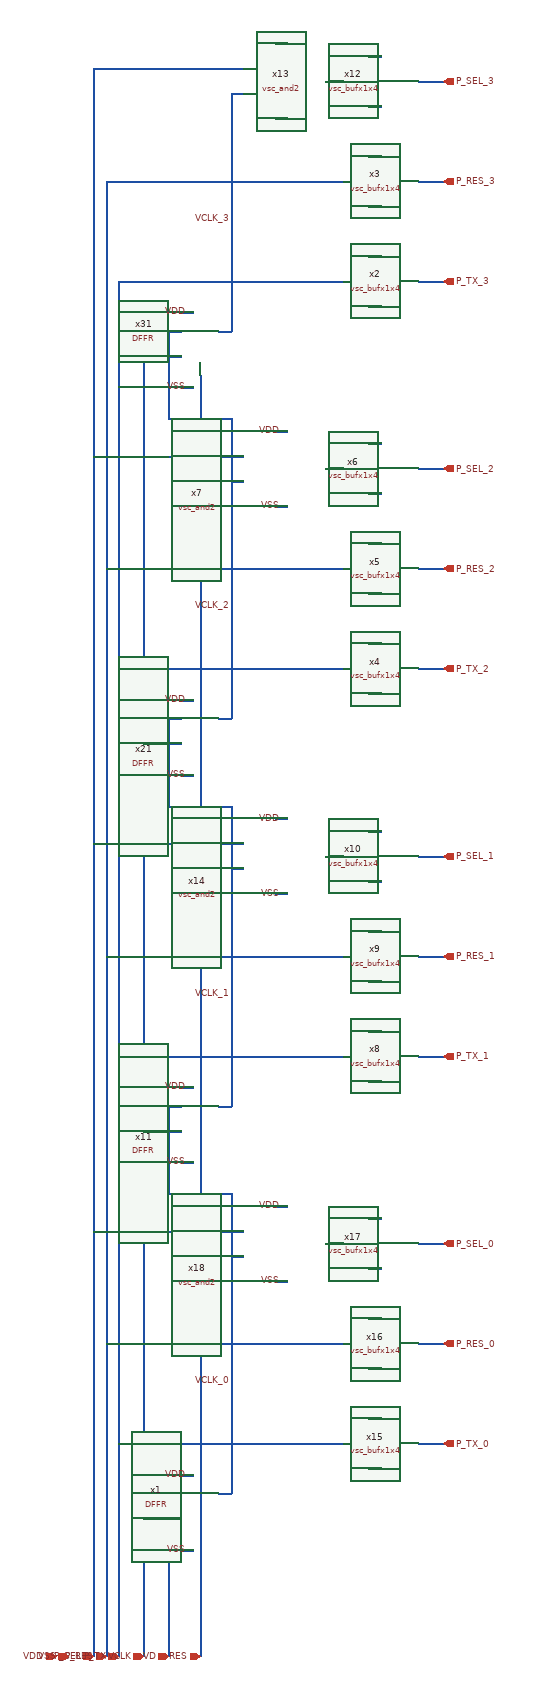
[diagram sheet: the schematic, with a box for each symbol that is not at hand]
v {xschem version=3.4.8RC file_version=1.2}
G {}
K {}
V {}
S {}
E {}
N 80 -2620 80 -80 {lab=P_SEL}
N 100 -2440 100 -80 {lab=P_RES}
N 120 -2280 120 -80 {lab=P_TX}
N 220 -370 240 -370 {lab=VDD}
N 220 -250 240 -250 {lab=VSS}
N 200 -340 200 -80 {lab=VD}
N 160 -2160 160 -80 {lab=VCLK}
N 250 -2130 250 -80 {lab=RES}
N 280 -340 300 -340 {lab=VCLK_0}
N 300 -820 300 -340 {lab=VCLK_0}
N 200 -340 220 -340 {lab=VD}
N 160 -300 220 -300 {lab=VCLK}
N 300 -720 320 -720 {lab=VCLK_0}
N 120 -420 480 -420 {lab=P_TX}
N 100 -580 480 -580 {lab=P_RES}
N 80 -760 320 -760 {lab=P_SEL}
N 600 -420 640 -420 {lab=P_TX_0}
N 600 -580 640 -580 {lab=P_RES_0}
N 600 -740 640 -740 {lab=P_SEL_0}
N 220 -990 240 -990 {lab=VDD}
N 220 -870 240 -870 {lab=VSS}
N 200 -820 300 -820 {lab=VCLK_0}
N 200 -960 200 -820 {lab=VCLK_0}
N 200 -960 220 -960 {lab=VCLK_0}
N 280 -960 300 -960 {lab=VCLK_1}
N 300 -1440 300 -960 {lab=VCLK_1}
N 300 -1340 320 -1340 {lab=VCLK_1}
N 120 -1040 480 -1040 {lab=P_TX}
N 100 -1200 480 -1200 {lab=P_RES}
N 80 -1380 320 -1380 {lab=P_SEL}
N 600 -1040 640 -1040 {lab=P_TX_1}
N 600 -1200 640 -1200 {lab=P_RES_1}
N 600 -1360 640 -1360 {lab=P_SEL_1}
N 220 -1610 240 -1610 {lab=VDD}
N 220 -1490 240 -1490 {lab=VSS}
N 200 -1440 300 -1440 {lab=VCLK_1}
N 200 -1580 200 -1440 {lab=VCLK_1}
N 200 -1580 220 -1580 {lab=VCLK_1}
N 280 -1580 300 -1580 {lab=VCLK_2}
N 300 -2060 300 -1580 {lab=VCLK_2}
N 300 -1960 320 -1960 {lab=VCLK_2}
N 120 -1660 480 -1660 {lab=P_TX}
N 100 -1820 480 -1820 {lab=P_RES}
N 80 -2000 320 -2000 {lab=P_SEL}
N 600 -1660 640 -1660 {lab=P_TX_2}
N 600 -1820 640 -1820 {lab=P_RES_2}
N 600 -1980 640 -1980 {lab=P_SEL_2}
N 220 -2230 240 -2230 {lab=VDD}
N 220 -2110 240 -2110 {lab=VSS}
N 200 -2060 300 -2060 {lab=VCLK_2}
N 200 -2200 200 -2060 {lab=VCLK_2}
N 200 -2200 220 -2200 {lab=VCLK_2}
N 280 -2200 300 -2200 {lab=VCLK_3}
N 300 -2580 300 -2200 {lab=VCLK_3}
N 370 -2540 390 -2540 {lab=VSS}
N 370 -2660 390 -2660 {lab=VDD}
N 300 -2580 320 -2580 {lab=VCLK_3}
N 120 -2280 480 -2280 {lab=P_TX}
N 100 -2440 480 -2440 {lab=P_RES}
N 80 -2620 320 -2620 {lab=P_SEL}
N 520 -2240 540 -2240 {lab=VSS}
N 520 -2320 540 -2320 {lab=VDD}
N 600 -2280 640 -2280 {lab=P_TX_3}
N 600 -2440 640 -2440 {lab=P_RES_3}
N 450 -2600 480 -2600 {lab=#net1}
N 600 -2600 640 -2600 {lab=P_SEL_3}
N 160 -2160 220 -2160 {lab=VCLK}
N 160 -1540 220 -1540 {lab=VCLK}
N 160 -920 220 -920 {lab=VCLK}
N 520 -2400 540 -2400 {lab=VSS}
N 520 -2480 540 -2480 {lab=VDD}
N 520 -2560 540 -2560 {lab=VSS}
N 520 -2640 540 -2640 {lab=VDD}
N 370 -1920 390 -1920 {lab=VSS}
N 370 -2040 390 -2040 {lab=VDD}
N 520 -1620 540 -1620 {lab=VSS}
N 520 -1700 540 -1700 {lab=VDD}
N 450 -1980 480 -1980 {lab=#net1}
N 520 -1780 540 -1780 {lab=VSS}
N 520 -1860 540 -1860 {lab=VDD}
N 520 -1940 540 -1940 {lab=VSS}
N 520 -2020 540 -2020 {lab=VDD}
N 370 -1300 390 -1300 {lab=VSS}
N 370 -1420 390 -1420 {lab=VDD}
N 520 -1000 540 -1000 {lab=VSS}
N 520 -1080 540 -1080 {lab=VDD}
N 450 -1360 480 -1360 {lab=#net1}
N 520 -1160 540 -1160 {lab=VSS}
N 520 -1240 540 -1240 {lab=VDD}
N 520 -1320 540 -1320 {lab=VSS}
N 520 -1400 540 -1400 {lab=VDD}
N 370 -680 390 -680 {lab=VSS}
N 370 -800 390 -800 {lab=VDD}
N 520 -380 540 -380 {lab=VSS}
N 520 -460 540 -460 {lab=VDD}
N 450 -740 480 -740 {lab=#net1}
N 520 -540 540 -540 {lab=VSS}
N 520 -620 540 -620 {lab=VDD}
N 520 -700 540 -700 {lab=VSS}
N 520 -780 540 -780 {lab=VDD}
C {devices/ipin.sym} 80 -80 3 0 {name=p1 lab=P_SEL}
C {devices/ipin.sym} 100 -80 3 0 {name=p2 lab=P_RES}
C {devices/ipin.sym} 120 -80 3 0 {name=p3 lab=P_TX}
C {devices/ipin.sym} 200 -80 3 0 {name=p4 lab=VD}
C {devices/ipin.sym} 160 -80 3 0 {name=p5 lab=VCLK}
C {devices/ipin.sym} 250 -80 3 0 {name=p6 lab=RES}
C {TR-1um_5_stdcell/DFFR.sym} 250 -310 0 0 {name=x1}
C {devices/iopin.sym} 20 -80 1 0 {name=p7 lab=VDD}
C {devices/iopin.sym} 40 -80 1 0 {name=p8 lab=VSS}
C {devices/lab_wire.sym} 230 -370 0 0 {name=p9 sig_type=std_logic lab=VDD}
C {devices/lab_wire.sym} 230 -250 2 1 {name=p10 sig_type=std_logic lab=VSS}
C {devices/opin.sym} 640 -420 0 0 {name=p21 lab=P_TX_0}
C {devices/opin.sym} 640 -580 0 0 {name=p26 lab=P_RES_0}
C {devices/opin.sym} 640 -740 0 0 {name=p31 lab=P_SEL_0}
C {TR-1um_5_stdcell/DFFR.sym} 250 -930 0 0 {name=x11}
C {devices/lab_wire.sym} 230 -990 0 0 {name=p32 sig_type=std_logic lab=VDD}
C {devices/lab_wire.sym} 230 -870 2 1 {name=p33 sig_type=std_logic lab=VSS}
C {devices/opin.sym} 640 -1040 0 0 {name=p44 lab=P_TX_1}
C {devices/opin.sym} 640 -1200 0 0 {name=p49 lab=P_RES_1}
C {devices/opin.sym} 640 -1360 0 0 {name=p54 lab=P_SEL_1}
C {TR-1um_5_stdcell/DFFR.sym} 250 -1550 0 0 {name=x21}
C {devices/lab_wire.sym} 230 -1610 0 0 {name=p55 sig_type=std_logic lab=VDD}
C {devices/lab_wire.sym} 230 -1490 2 1 {name=p56 sig_type=std_logic lab=VSS}
C {devices/opin.sym} 640 -1660 0 0 {name=p67 lab=P_TX_2}
C {devices/opin.sym} 640 -1820 0 0 {name=p72 lab=P_RES_2}
C {devices/opin.sym} 640 -1980 0 0 {name=p77 lab=P_SEL_2}
C {TR-1um_5_stdcell/DFFR.sym} 250 -2170 0 0 {name=x31}
C {devices/lab_wire.sym} 230 -2230 0 0 {name=p78 sig_type=std_logic lab=VDD}
C {devices/lab_wire.sym} 230 -2110 2 1 {name=p79 sig_type=std_logic lab=VSS}
C {devices/lab_wire.sym} 380 -2540 2 1 {name=p84 sig_type=std_logic lab=VSS}
C {devices/lab_wire.sym} 380 -2660 0 0 {name=p85 sig_type=std_logic lab=VDD}
C {devices/lab_wire.sym} 530 -2240 2 1 {name=p86 sig_type=std_logic lab=VSS}
C {devices/lab_wire.sym} 530 -2320 0 0 {name=p87 sig_type=std_logic lab=VDD}
C {devices/opin.sym} 640 -2280 0 0 {name=p90 lab=P_TX_3}
C {devices/opin.sym} 640 -2440 0 0 {name=p95 lab=P_RES_3}
C {devices/opin.sym} 640 -2600 0 0 {name=p100 lab=P_SEL_3}
C {devices/lab_wire.sym} 300 -520 3 0 {name=p101 sig_type=std_logic lab=VCLK_0}
C {devices/lab_wire.sym} 300 -1140 3 0 {name=p102 sig_type=std_logic lab=VCLK_1}
C {devices/lab_wire.sym} 300 -1760 3 0 {name=p103 sig_type=std_logic lab=VCLK_2}
C {devices/lab_wire.sym} 300 -2380 3 0 {name=p104 sig_type=std_logic lab=VCLK_3}
C {2026_imager/vsc_bufx1x4.sym} 500 -2280 0 0 {name=x2}
C {devices/lab_wire.sym} 530 -2400 2 1 {name=p11 sig_type=std_logic lab=VSS}
C {devices/lab_wire.sym} 530 -2480 0 0 {name=p12 sig_type=std_logic lab=VDD}
C {2026_imager/vsc_bufx1x4.sym} 500 -2440 0 0 {name=x3}
C {devices/lab_wire.sym} 530 -2560 2 1 {name=p13 sig_type=std_logic lab=VSS}
C {devices/lab_wire.sym} 530 -2640 0 0 {name=p14 sig_type=std_logic lab=VDD}
C {2026_imager/vsc_bufx1x4.sym} 500 -2600 0 0 {name=x12}
C {2026_imager/vsc_and2.sym} 340 -2600 0 0 {name=x13}
C {devices/lab_wire.sym} 380 -1920 2 1 {name=p15 sig_type=std_logic lab=VSS}
C {devices/lab_wire.sym} 380 -2040 0 0 {name=p16 sig_type=std_logic lab=VDD}
C {devices/lab_wire.sym} 530 -1620 2 1 {name=p17 sig_type=std_logic lab=VSS}
C {devices/lab_wire.sym} 530 -1700 0 0 {name=p18 sig_type=std_logic lab=VDD}
C {2026_imager/vsc_bufx1x4.sym} 500 -1660 0 0 {name=x4}
C {devices/lab_wire.sym} 530 -1780 2 1 {name=p19 sig_type=std_logic lab=VSS}
C {devices/lab_wire.sym} 530 -1860 0 0 {name=p20 sig_type=std_logic lab=VDD}
C {2026_imager/vsc_bufx1x4.sym} 500 -1820 0 0 {name=x5}
C {devices/lab_wire.sym} 530 -1940 2 1 {name=p22 sig_type=std_logic lab=VSS}
C {devices/lab_wire.sym} 530 -2020 0 0 {name=p23 sig_type=std_logic lab=VDD}
C {2026_imager/vsc_bufx1x4.sym} 500 -1980 0 0 {name=x6}
C {2026_imager/vsc_and2.sym} 340 -1980 0 0 {name=x7}
C {devices/lab_wire.sym} 380 -1300 2 1 {name=p24 sig_type=std_logic lab=VSS}
C {devices/lab_wire.sym} 380 -1420 0 0 {name=p25 sig_type=std_logic lab=VDD}
C {devices/lab_wire.sym} 530 -1000 2 1 {name=p27 sig_type=std_logic lab=VSS}
C {devices/lab_wire.sym} 530 -1080 0 0 {name=p28 sig_type=std_logic lab=VDD}
C {2026_imager/vsc_bufx1x4.sym} 500 -1040 0 0 {name=x8}
C {devices/lab_wire.sym} 530 -1160 2 1 {name=p29 sig_type=std_logic lab=VSS}
C {devices/lab_wire.sym} 530 -1240 0 0 {name=p30 sig_type=std_logic lab=VDD}
C {2026_imager/vsc_bufx1x4.sym} 500 -1200 0 0 {name=x9}
C {devices/lab_wire.sym} 530 -1320 2 1 {name=p34 sig_type=std_logic lab=VSS}
C {devices/lab_wire.sym} 530 -1400 0 0 {name=p35 sig_type=std_logic lab=VDD}
C {2026_imager/vsc_bufx1x4.sym} 500 -1360 0 0 {name=x10}
C {2026_imager/vsc_and2.sym} 340 -1360 0 0 {name=x14}
C {devices/lab_wire.sym} 380 -680 2 1 {name=p36 sig_type=std_logic lab=VSS}
C {devices/lab_wire.sym} 380 -800 0 0 {name=p37 sig_type=std_logic lab=VDD}
C {devices/lab_wire.sym} 530 -380 2 1 {name=p38 sig_type=std_logic lab=VSS}
C {devices/lab_wire.sym} 530 -460 0 0 {name=p39 sig_type=std_logic lab=VDD}
C {2026_imager/vsc_bufx1x4.sym} 500 -420 0 0 {name=x15}
C {devices/lab_wire.sym} 530 -540 2 1 {name=p40 sig_type=std_logic lab=VSS}
C {devices/lab_wire.sym} 530 -620 0 0 {name=p41 sig_type=std_logic lab=VDD}
C {2026_imager/vsc_bufx1x4.sym} 500 -580 0 0 {name=x16}
C {devices/lab_wire.sym} 530 -700 2 1 {name=p42 sig_type=std_logic lab=VSS}
C {devices/lab_wire.sym} 530 -780 0 0 {name=p43 sig_type=std_logic lab=VDD}
C {2026_imager/vsc_bufx1x4.sym} 500 -740 0 0 {name=x17}
C {2026_imager/vsc_and2.sym} 340 -740 0 0 {name=x18}
